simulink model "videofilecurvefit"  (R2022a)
settings: Solver=FixedStepAuto  StartTime=0.0  StopTime=10.0  RelTol=1e-3  EnableMultiTasking=on
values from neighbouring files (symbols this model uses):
  line = zeros(size(bw),'like',bw)    [CurveDetectionSystem.m]
undefined symbols (not defined in the file or in its folder): Drive, MATLAB, part2_chap3
libraries: visionconversions x2, dspvision x2, visiontextngfix x1

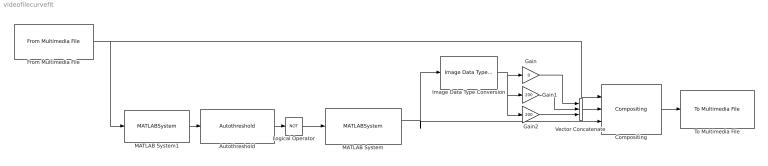
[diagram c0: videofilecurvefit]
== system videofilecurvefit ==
  Autothreshold : visionconversions/Autothreshold  operator=>  threshOut=off  effMetricOut=off  userDefinedRange=off  umin=0  umax=255  outOfRngOpt=Ignore  scaleThreshold=off  scaleFactor=1  roundingMode=Floor  overflowMode=off  P1Mode=Specify word length  P1WordLength=32  P1FracLength=30  P2Mode=Specify word length  P2WordLength=32  P2FracLength=22  P3Mode=Specify word length  P3WordLength=32  P3FracLength=14  P4Mode=Binary point scaling  P4WordLength=32  P4FracLength=15  Q1Mode=Specify word length  Q1WordLength=32  Q1FracLength=16  EMMode=Specify word length  EMWordLength=16  EMFracLength=14
  Compositing : visiontextngfix/Compositing  operation=Binary mask  bFacSrc=Specify via dialog  bFactor=0.5  mFacSrc=Input port  mFactor=1  source=Specify via dialog  coordinates=[1 1]  roundingMode=Floor  overflowMode=off  prodOutputMode=Binary point scaling  prodOutputWordLength=32  prodOutputFracLength=10
  From Multimedia File : dspvision/From Multimedia File  inputFilename=/MATLAB Drive/part2_chap3/line.avi  readRange=[1 Inf]  loop=on  numPlays=inf  outputStreams=ビデオのみ  videoDataType=double  audioDataType=int16  inheritSampleTime=on  userDefinedSampleTime=1/30  noAudioOutput=off  isIntensityVideo=off  fourcc=RGB  colorVideoFormat=One multidimensional signal  outputEOF=off  dataOrg=Column-major  audioFrameSize=1024  computeAudioFrameSize=off  outSamplingMode=Sample based
  Gain : Gain  Gain=0  ParamDataTypeStr=uint8  OutDataTypeStr=double
  Gain1 : Gain  Gain=200  ParamDataTypeStr=uint8  OutDataTypeStr=double
  Gain2 : Gain  Gain=200  ParamDataTypeStr=uint8  OutDataTypeStr=double
  Image Data Type Conversion : visionconversions/Image Data Type Conversion  outDT=single  isSigned=on  wordLen=16  numFracBits=0
  Logical Operator : Logic  Operator=NOT  AllPortsSameDT=off  OutDataTypeStr=boolean
  MATLAB System : MATLABSystem  System=CurveDetectionSystem  Degree=3  SimulateUsing=Code generation
  MATLAB System1 : MATLABSystem  System=Rgb2GraySystem  SimulateUsing=Code generation
  To Multimedia File : dspvision/To Multimedia File  outputFilename=output.avi  streamSelection=Video only  videoCompressor=None (uncompressed)  audioCompressor=None (uncompressed)  imagePorts=One multidimensional signal  fileType=AVI  audioDatatype=Determine from input data type  fourcc=RGB  videoQuality=75  mj2000CompFactor=10
  Vector Concatenate : Concatenate  NumInputs=3  Mode=Multidimensional array  ConcatenateDimension=3
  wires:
  Autothreshold/1 -> Logical Operator/1
  Compositing/1 -> To Multimedia File/1
  Logical Operator/1 -> MATLAB System/1
  MATLAB System/1 -> Compositing/3, Image Data Type Conversion/1
  Gain/1 -> Vector Concatenate/1
  Gain2/1 -> Vector Concatenate/3
  Gain1/1 -> Vector Concatenate/2
  Vector Concatenate/1 -> Compositing/2
  MATLAB System1/1 -> Autothreshold/1
  Image Data Type Conversion/1 -> Gain1/1, Gain2/1, Gain/1
  From Multimedia File/1 -> Compositing/1, MATLAB System1/1
